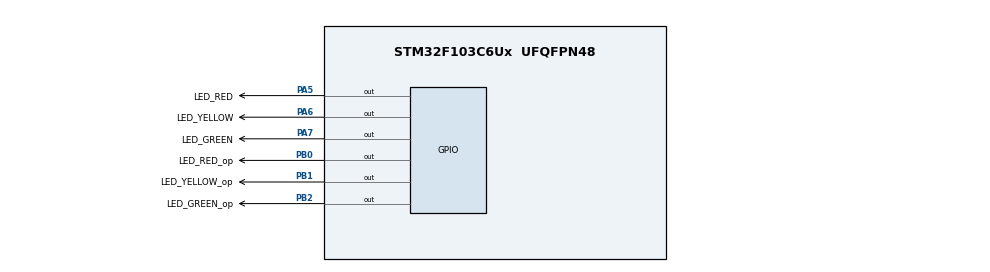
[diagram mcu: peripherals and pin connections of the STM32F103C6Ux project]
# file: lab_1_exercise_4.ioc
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Mcu.Family=STM32F1
Mcu.Name=STM32F103C6Ux
Mcu.Package=UFQFPN48
NVIC.PriorityGroup=NVIC_PRIORITYGROUP_4
PA5.GPIO_Label=LED_RED
PA5.Signal=GPIO_Output
PA6.GPIO_Label=LED_YELLOW
PA6.Signal=GPIO_Output
PA7.GPIO_Label=LED_GREEN
PA7.Signal=GPIO_Output
PB0.GPIO_Label=LED_RED_op
PB0.Signal=GPIO_Output
PB1.GPIO_Label=LED_YELLOW_op
PB1.Signal=GPIO_Output
PB2.GPIO_Label=LED_GREEN_op
PB2.Signal=GPIO_Output
ProjectManager.HeapSize=0x200
ProjectManager.StackSize=0x400
ProjectManager.TargetToolchain=STM32CubeIDE
RCC.APB1Freq_Value=8000000
RCC.APB2Freq_Value=8000000
VP_SYS_VS_ND.Mode=No_Debug
board=custom

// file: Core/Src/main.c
/* USER CODE BEGIN Header */
/**
  ******************************************************************************
  * @file           : main.c
  * @brief          : Main program body
  ******************************************************************************
  * @attention
  *
  * <h2><center>&copy; Copyright (c) 2026 STMicroelectronics.
  * All rights reserved.</center></h2>
  *
  * This software component is licensed by ST under BSD 3-Clause license,
  * the "License"; You may not use this file except in compliance with the
  * License. You may obtain a copy of the License at:
  *                        opensource.org/licenses/BSD-3-Clause
  *
  ******************************************************************************
  */
/* USER CODE END Header */
#include "main.h"

void SystemClock_Config(void);
static void MX_GPIO_Init(void);

/* USER CODE BEGIN 0 */

void display7SEG(int num)
{
    switch (num)
    {
        case 0:
            HAL_GPIO_WritePin(SEG_GPIO_Port, a_Pin, 0);
            HAL_GPIO_WritePin(SEG_GPIO_Port, b_Pin, 0);
            HAL_GPIO_WritePin(SEG_GPIO_Port, c_Pin, 0);
            HAL_GPIO_WritePin(SEG_GPIO_Port, d_Pin, 0);
            HAL_GPIO_WritePin(SEG_GPIO_Port, e_Pin, 0);
            HAL_GPIO_WritePin(SEG_GPIO_Port, f_Pin, 0);
            HAL_GPIO_WritePin(SEG_GPIO_Port, g_Pin, 1);
            break;
        case 1:
            HAL_GPIO_WritePin(SEG_GPIO_Port, a_Pin, 1);
            HAL_GPIO_WritePin(SEG_GPIO_Port, b_Pin, 0);
            HAL_GPIO_WritePin(SEG_GPIO_Port, c_Pin, 0);
            HAL_GPIO_WritePin(SEG_GPIO_Port, d_Pin, 1);
            HAL_GPIO_WritePin(SEG_GPIO_Port, e_Pin, 1);
            HAL_GPIO_WritePin(SEG_GPIO_Port, f_Pin, 1);
            HAL_GPIO_WritePin(SEG_GPIO_Port, g_Pin, 1);
            break;
        case 2:
            HAL_GPIO_WritePin(SEG_GPIO_Port, a_Pin, 0);
            HAL_GPIO_WritePin(SEG_GPIO_Port, b_Pin, 0);
            HAL_GPIO_WritePin(SEG_GPIO_Port, c_Pin, 1);
            HAL_GPIO_WritePin(SEG_GPIO_Port, d_Pin, 0);
            HAL_GPIO_WritePin(SEG_GPIO_Port, e_Pin, 0);
            HAL_GPIO_WritePin(SEG_GPIO_Port, f_Pin, 1);
            HAL_GPIO_WritePin(SEG_GPIO_Port, g_Pin, 0);
            break;
        case 3:
            HAL_GPIO_WritePin(SEG_GPIO_Port, a_Pin, 0);
            HAL_GPIO_WritePin(SEG_GPIO_Port, b_Pin, 0);
            HAL_GPIO_WritePin(SEG_GPIO_Port, c_Pin, 0);
            HAL_GPIO_WritePin(SEG_GPIO_Port, d_Pin, 0);
            HAL_GPIO_WritePin(SEG_GPIO_Port, e_Pin, 1);
            HAL_GPIO_WritePin(SEG_GPIO_Port, f_Pin, 1);
            HAL_GPIO_WritePin(SEG_GPIO_Port, g_Pin, 0);
            break;
        case 4:
            HAL_GPIO_WritePin(SEG_GPIO_Port, a_Pin, 1);
            HAL_GPIO_WritePin(SEG_GPIO_Port, b_Pin, 0);
            HAL_GPIO_WritePin(SEG_GPIO_Port, c_Pin, 0);
            HAL_GPIO_WritePin(SEG_GPIO_Port, d_Pin, 1);
            HAL_GPIO_WritePin(SEG_GPIO_Port, e_Pin, 1);
            HAL_GPIO_WritePin(SEG_GPIO_Port, f_Pin, 0);
            HAL_GPIO_WritePin(SEG_GPIO_Port, g_Pin, 0);
            break;
        case 5:
            HAL_GPIO_WritePin(SEG_GPIO_Port, a_Pin, 0);
            HAL_GPIO_WritePin(SEG_GPIO_Port, b_Pin, 1);
            HAL_GPIO_WritePin(SEG_GPIO_Port, c_Pin, 0);
            HAL_GPIO_WritePin(SEG_GPIO_Port, d_Pin, 0);
            HAL_GPIO_WritePin(SEG_GPIO_Port, e_Pin, 1);
            HAL_GPIO_WritePin(SEG_GPIO_Port, f_Pin, 0);
            HAL_GPIO_WritePin(SEG_GPIO_Port, g_Pin, 0);
            break;
        case 6:
            HAL_GPIO_WritePin(SEG_GPIO_Port, a_Pin, 0);
            HAL_GPIO_WritePin(SEG_GPIO_Port, b_Pin, 1);
            HAL_GPIO_WritePin(SEG_GPIO_Port, c_Pin, 0);
            HAL_GPIO_WritePin(SEG_GPIO_Port, d_Pin, 0);
            HAL_GPIO_WritePin(SEG_GPIO_Port, e_Pin, 0);
            HAL_GPIO_WritePin(SEG_GPIO_Port, f_Pin, 0);
            HAL_GPIO_WritePin(SEG_GPIO_Port, g_Pin, 0);
            break;
        case 7:
            HAL_GPIO_WritePin(SEG_GPIO_Port, a_Pin, 0);
            HAL_GPIO_WritePin(SEG_GPIO_Port, b_Pin, 0);
            HAL_GPIO_WritePin(SEG_GPIO_Port, c_Pin, 0);
            HAL_GPIO_WritePin(SEG_GPIO_Port, d_Pin, 1);
            HAL_GPIO_WritePin(SEG_GPIO_Port, e_Pin, 1);
            HAL_GPIO_WritePin(SEG_GPIO_Port, f_Pin, 1);
            HAL_GPIO_WritePin(SEG_GPIO_Port, g_Pin, 1);
            break;
        case 8:
            HAL_GPIO_WritePin(SEG_GPIO_Port, a_Pin, 0);
            HAL_GPIO_WritePin(SEG_GPIO_Port, b_Pin, 0);
            HAL_GPIO_WritePin(SEG_GPIO_Port, c_Pin, 0);
            HAL_GPIO_WritePin(SEG_GPIO_Port, d_Pin, 0);
            HAL_GPIO_WritePin(SEG_GPIO_Port, e_Pin, 0);
            HAL_GPIO_WritePin(SEG_GPIO_Port, f_Pin, 0);
            HAL_GPIO_WritePin(SEG_GPIO_Port, g_Pin, 0);
            break;
        case 9:
            HAL_GPIO_WritePin(SEG_GPIO_Port, a_Pin, 0);
            HAL_GPIO_WritePin(SEG_GPIO_Port, b_Pin, 0);
            HAL_GPIO_WritePin(SEG_GPIO_Port, c_Pin, 0);
            HAL_GPIO_WritePin(SEG_GPIO_Port, d_Pin, 0);
            HAL_GPIO_WritePin(SEG_GPIO_Port, e_Pin, 1);
            HAL_GPIO_WritePin(SEG_GPIO_Port, f_Pin, 0);
            HAL_GPIO_WritePin(SEG_GPIO_Port, g_Pin, 0);
            break;
        default:
            break;
    }
}

/* USER CODE END 0 */

int main(void)
{

  /* MCU Configuration--------------------------------------------------------*/

  /* Reset of all peripherals, Initializes the Flash interface and the Systick. */
  HAL_Init();

  /* Configure the system clock */
  SystemClock_Config();

  /* Initialize all configured peripherals */
  MX_GPIO_Init();
  /* USER CODE BEGIN 2 */
  int counter = 0;
  /* USER CODE END 2 */

  /* Infinite loop */
  while (1)
  {
    if (counter >= 10) counter = 0;
    display7SEG(counter++);
    HAL_Delay(1000);
  }
}

void SystemClock_Config(void)
{
  RCC_OscInitTypeDef RCC_OscInitStruct = {0};
  RCC_ClkInitTypeDef RCC_ClkInitStruct = {0};

  /** Initializes the RCC Oscillators according to the specified parameters
  * in the RCC_OscInitTypeDef structure.
  */
  RCC_OscInitStruct.OscillatorType = RCC_OSCILLATORTYPE_HSI;
  RCC_OscInitStruct.HSIState = RCC_HSI_ON;
  RCC_OscInitStruct.HSICalibrationValue = RCC_HSICALIBRATION_DEFAULT;
  RCC_OscInitStruct.PLL.PLLState = RCC_PLL_NONE;
  if (HAL_RCC_OscConfig(&RCC_OscInitStruct) != HAL_OK)
  {
    Error_Handler();
  }
  /** Initializes the CPU, AHB and APB buses clocks
  */
  RCC_ClkInitStruct.ClockType = RCC_CLOCKTYPE_HCLK|RCC_CLOCKTYPE_SYSCLK
                              |RCC_CLOCKTYPE_PCLK1|RCC_CLOCKTYPE_PCLK2;
  RCC_ClkInitStruct.SYSCLKSource = RCC_SYSCLKSOURCE_HSI;
  RCC_ClkInitStruct.AHBCLKDivider = RCC_SYSCLK_DIV1;
  RCC_ClkInitStruct.APB1CLKDivider = RCC_HCLK_DIV1;
  RCC_ClkInitStruct.APB2CLKDivider = RCC_HCLK_DIV1;

  if (HAL_RCC_ClockConfig(&RCC_ClkInitStruct, FLASH_LATENCY_0) != HAL_OK)
  {
    Error_Handler();
  }
}

static void MX_GPIO_Init(void)
{
  GPIO_InitTypeDef GPIO_InitStruct = {0};

  /* GPIO Ports Clock Enable */
  __HAL_RCC_GPIOB_CLK_ENABLE();

  /*Configure GPIO pin Output Level - all segments OFF (common-anode: SET=OFF) */
  HAL_GPIO_WritePin(SEG_GPIO_Port, a_Pin|b_Pin|c_Pin|d_Pin|e_Pin|f_Pin|g_Pin, GPIO_PIN_SET);

  /*Configure GPIO pins : PB0(a) PB1(b) PB2(c) PB3(d) PB4(e) PB5(f) PB6(g) */
  GPIO_InitStruct.Pin = a_Pin|b_Pin|c_Pin|d_Pin|e_Pin|f_Pin|g_Pin;
  GPIO_InitStruct.Mode = GPIO_MODE_OUTPUT_PP;
  GPIO_InitStruct.Pull = GPIO_NOPULL;
  GPIO_InitStruct.Speed = GPIO_SPEED_FREQ_LOW;
  HAL_GPIO_Init(SEG_GPIO_Port, &GPIO_InitStruct);

}

void Error_Handler(void)
{
  __disable_irq();
  while (1)
  {
  }
}

/************************ (C) COPYRIGHT STMicroelectronics *****END OF FILE****/
